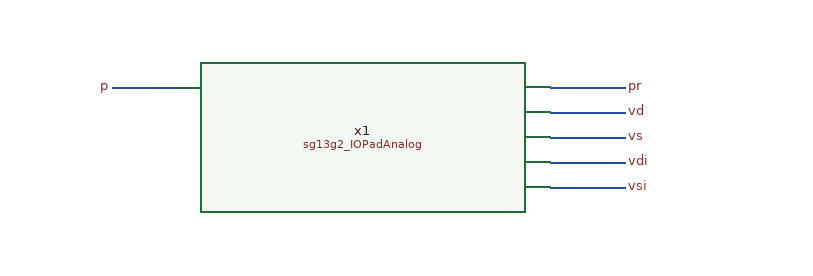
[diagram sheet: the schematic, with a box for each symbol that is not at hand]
v {xschem version=3.4.5 file_version=1.2
}
G {}
K {}
V {}
S {}
E {}
N 350 -670 400 -670 {
lab=p}
N 700 -670 760 -670 {
lab=pr}
N 700 -650 760 -650 {
lab=vd}
N 700 -630 760 -630 {
lab=vs}
N 700 -610 760 -610 {
lab=vdi}
N 700 -590 760 -590 {
lab=vsi}
C {title.sym} 160 -40 0 0 {name=l1 author="Boris Murmann"}
C {/home/bmurmann/eda/designs/EE628/5_Design/3_Real_circuits/sg13g2_IOPadAnalog.sym} 550 -630 0 0 {name=x1}
C {lab_wire.sym} 760 -670 0 1 {name=p1 sig_type=std_logic lab=pr}
C {lab_wire.sym} 760 -650 0 1 {name=p2 sig_type=std_logic lab=vd}
C {lab_wire.sym} 760 -630 0 1 {name=p3 sig_type=std_logic lab=vs}
C {lab_wire.sym} 760 -610 0 1 {name=p4 sig_type=std_logic lab=vdi}
C {lab_wire.sym} 760 -590 0 1 {name=p5 sig_type=std_logic lab=vsi}
C {lab_wire.sym} 350 -670 0 0 {name=p6 sig_type=std_logic lab=p}
